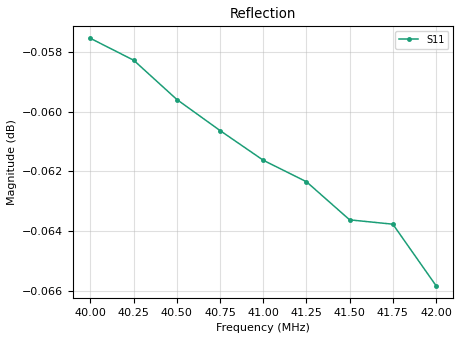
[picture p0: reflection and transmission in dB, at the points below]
# Hz S RI R 50
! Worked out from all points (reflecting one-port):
!   9 points, 40 MHz to 42 MHz, reference 50 ohm
!   lowest |S11| = -0.1 dB at 42 MHz (marker M1), VSWR 265.84, Z = 0.286 - j36.1 ohm
!   phase of S11 starts at -103 deg and turns -5 deg over the sweep
4e7  -0.2262 -0.9673
4.025e7  -0.2371 -0.9646
4.05e7  -0.248 -0.9617
4.075e7  -0.2589 -0.9587
4.1e7  -0.2697 -0.9556
4.125e7  -0.2805 -0.9524
4.15e7  -0.2913 -0.949
4.175e7  -0.3021 -0.9456
4.2e7  -0.3127 -0.9419
